VERSION 5.7 ;
BUSBITCHARS "[]" ;
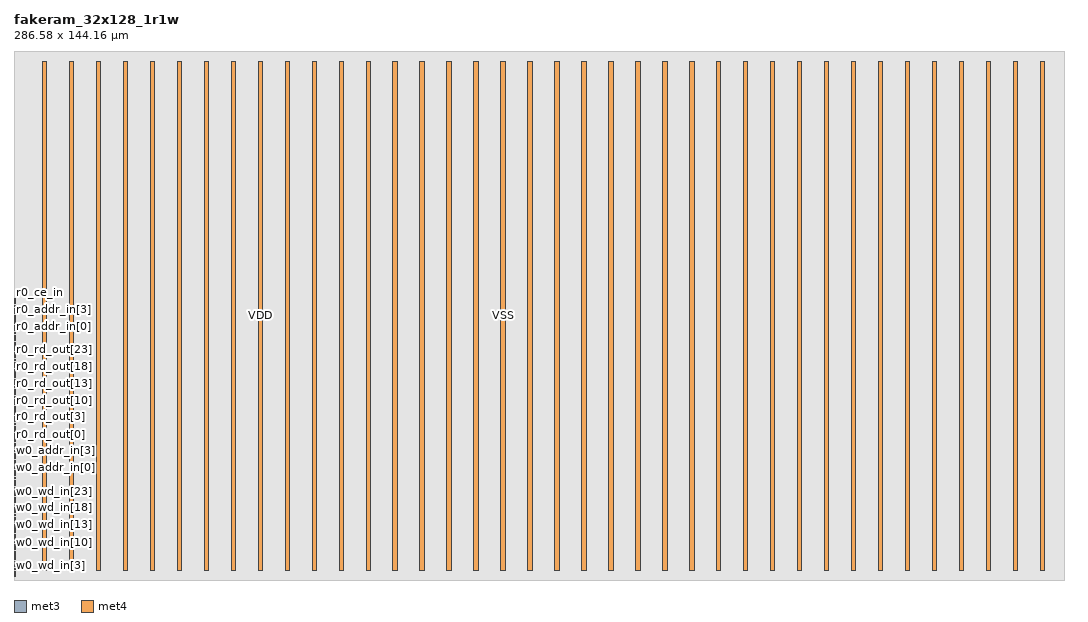
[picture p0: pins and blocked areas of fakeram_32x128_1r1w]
MACRO fakeram_32x128_1r1w
  FOREIGN fakeram_32x128_1r1w 0 0 ;
  SYMMETRY X Y R90 ;
  SIZE 286.580 BY 144.160 ;
  CLASS BLOCK ;
  PIN w0_wd_in[0]
    DIRECTION INPUT ;
    USE SIGNAL ;
    SHAPE ABUTMENT ;
    PORT
      LAYER met3 ;
      RECT 0.000 0.920 0.500 1.420 ;
    END
  END w0_wd_in[0]
  PIN w0_wd_in[1]
    DIRECTION INPUT ;
    USE SIGNAL ;
    SHAPE ABUTMENT ;
    PORT
      LAYER met3 ;
      RECT 0.000 1.840 0.500 2.340 ;
    END
  END w0_wd_in[1]
  PIN w0_wd_in[2]
    DIRECTION INPUT ;
    USE SIGNAL ;
    SHAPE ABUTMENT ;
    PORT
      LAYER met3 ;
      RECT 0.000 2.760 0.500 3.260 ;
    END
  END w0_wd_in[2]
  PIN w0_wd_in[3]
    DIRECTION INPUT ;
    USE SIGNAL ;
    SHAPE ABUTMENT ;
    PORT
      LAYER met3 ;
      RECT 0.000 3.680 0.500 4.180 ;
    END
  END w0_wd_in[3]
  PIN w0_wd_in[4]
    DIRECTION INPUT ;
    USE SIGNAL ;
    SHAPE ABUTMENT ;
    PORT
      LAYER met3 ;
      RECT 0.000 4.600 0.500 5.100 ;
    END
  END w0_wd_in[4]
  PIN w0_wd_in[5]
    DIRECTION INPUT ;
    USE SIGNAL ;
    SHAPE ABUTMENT ;
    PORT
      LAYER met3 ;
      RECT 0.000 5.520 0.500 6.020 ;
    END
  END w0_wd_in[5]
  PIN w0_wd_in[6]
    DIRECTION INPUT ;
    USE SIGNAL ;
    SHAPE ABUTMENT ;
    PORT
      LAYER met3 ;
      RECT 0.000 6.440 0.500 6.940 ;
    END
  END w0_wd_in[6]
  PIN w0_wd_in[7]
    DIRECTION INPUT ;
    USE SIGNAL ;
    SHAPE ABUTMENT ;
    PORT
      LAYER met3 ;
      RECT 0.000 7.360 0.500 7.860 ;
    END
  END w0_wd_in[7]
  PIN w0_wd_in[8]
    DIRECTION INPUT ;
    USE SIGNAL ;
    SHAPE ABUTMENT ;
    PORT
      LAYER met3 ;
      RECT 0.000 8.280 0.500 8.780 ;
    END
  END w0_wd_in[8]
  PIN w0_wd_in[9]
    DIRECTION INPUT ;
    USE SIGNAL ;
    SHAPE ABUTMENT ;
    PORT
      LAYER met3 ;
      RECT 0.000 9.200 0.500 9.700 ;
    END
  END w0_wd_in[9]
  PIN w0_wd_in[10]
    DIRECTION INPUT ;
    USE SIGNAL ;
    SHAPE ABUTMENT ;
    PORT
      LAYER met3 ;
      RECT 0.000 10.120 0.500 10.620 ;
    END
  END w0_wd_in[10]
  PIN w0_wd_in[11]
    DIRECTION INPUT ;
    USE SIGNAL ;
    SHAPE ABUTMENT ;
    PORT
      LAYER met3 ;
      RECT 0.000 11.040 0.500 11.540 ;
    END
  END w0_wd_in[11]
  PIN w0_wd_in[12]
    DIRECTION INPUT ;
    USE SIGNAL ;
    SHAPE ABUTMENT ;
    PORT
      LAYER met3 ;
      RECT 0.000 11.960 0.500 12.460 ;
    END
  END w0_wd_in[12]
  PIN w0_wd_in[13]
    DIRECTION INPUT ;
    USE SIGNAL ;
    SHAPE ABUTMENT ;
    PORT
      LAYER met3 ;
      RECT 0.000 12.880 0.500 13.380 ;
    END
  END w0_wd_in[13]
  PIN w0_wd_in[14]
    DIRECTION INPUT ;
    USE SIGNAL ;
    SHAPE ABUTMENT ;
    PORT
      LAYER met3 ;
      RECT 0.000 13.800 0.500 14.300 ;
    END
  END w0_wd_in[14]
  PIN w0_wd_in[15]
    DIRECTION INPUT ;
    USE SIGNAL ;
    SHAPE ABUTMENT ;
    PORT
      LAYER met3 ;
      RECT 0.000 14.720 0.500 15.220 ;
    END
  END w0_wd_in[15]
  PIN w0_wd_in[16]
    DIRECTION INPUT ;
    USE SIGNAL ;
    SHAPE ABUTMENT ;
    PORT
      LAYER met3 ;
      RECT 0.000 15.640 0.500 16.140 ;
    END
  END w0_wd_in[16]
  PIN w0_wd_in[17]
    DIRECTION INPUT ;
    USE SIGNAL ;
    SHAPE ABUTMENT ;
    PORT
      LAYER met3 ;
      RECT 0.000 16.560 0.500 17.060 ;
    END
  END w0_wd_in[17]
  PIN w0_wd_in[18]
    DIRECTION INPUT ;
    USE SIGNAL ;
    SHAPE ABUTMENT ;
    PORT
      LAYER met3 ;
      RECT 0.000 17.480 0.500 17.980 ;
    END
  END w0_wd_in[18]
  PIN w0_wd_in[19]
    DIRECTION INPUT ;
    USE SIGNAL ;
    SHAPE ABUTMENT ;
    PORT
      LAYER met3 ;
      RECT 0.000 18.400 0.500 18.900 ;
    END
  END w0_wd_in[19]
  PIN w0_wd_in[20]
    DIRECTION INPUT ;
    USE SIGNAL ;
    SHAPE ABUTMENT ;
    PORT
      LAYER met3 ;
      RECT 0.000 19.320 0.500 19.820 ;
    END
  END w0_wd_in[20]
  PIN w0_wd_in[21]
    DIRECTION INPUT ;
    USE SIGNAL ;
    SHAPE ABUTMENT ;
    PORT
      LAYER met3 ;
      RECT 0.000 20.240 0.500 20.740 ;
    END
  END w0_wd_in[21]
  PIN w0_wd_in[22]
    DIRECTION INPUT ;
    USE SIGNAL ;
    SHAPE ABUTMENT ;
    PORT
      LAYER met3 ;
      RECT 0.000 21.160 0.500 21.660 ;
    END
  END w0_wd_in[22]
  PIN w0_wd_in[23]
    DIRECTION INPUT ;
    USE SIGNAL ;
    SHAPE ABUTMENT ;
    PORT
      LAYER met3 ;
      RECT 0.000 22.080 0.500 22.580 ;
    END
  END w0_wd_in[23]
  PIN w0_wd_in[24]
    DIRECTION INPUT ;
    USE SIGNAL ;
    SHAPE ABUTMENT ;
    PORT
      LAYER met3 ;
      RECT 0.000 23.000 0.500 23.500 ;
    END
  END w0_wd_in[24]
  PIN w0_wd_in[25]
    DIRECTION INPUT ;
    USE SIGNAL ;
    SHAPE ABUTMENT ;
    PORT
      LAYER met3 ;
      RECT 0.000 23.920 0.500 24.420 ;
    END
  END w0_wd_in[25]
  PIN w0_wd_in[26]
    DIRECTION INPUT ;
    USE SIGNAL ;
    SHAPE ABUTMENT ;
    PORT
      LAYER met3 ;
      RECT 0.000 24.840 0.500 25.340 ;
    END
  END w0_wd_in[26]
  PIN w0_wd_in[27]
    DIRECTION INPUT ;
    USE SIGNAL ;
    SHAPE ABUTMENT ;
    PORT
      LAYER met3 ;
      RECT 0.000 25.760 0.500 26.260 ;
    END
  END w0_wd_in[27]
  PIN w0_wd_in[28]
    DIRECTION INPUT ;
    USE SIGNAL ;
    SHAPE ABUTMENT ;
    PORT
      LAYER met3 ;
      RECT 0.000 26.680 0.500 27.180 ;
    END
  END w0_wd_in[28]
  PIN w0_wd_in[29]
    DIRECTION INPUT ;
    USE SIGNAL ;
    SHAPE ABUTMENT ;
    PORT
      LAYER met3 ;
      RECT 0.000 27.600 0.500 28.100 ;
    END
  END w0_wd_in[29]
  PIN w0_wd_in[30]
    DIRECTION INPUT ;
    USE SIGNAL ;
    SHAPE ABUTMENT ;
    PORT
      LAYER met3 ;
      RECT 0.000 28.520 0.500 29.020 ;
    END
  END w0_wd_in[30]
  PIN w0_wd_in[31]
    DIRECTION INPUT ;
    USE SIGNAL ;
    SHAPE ABUTMENT ;
    PORT
      LAYER met3 ;
      RECT 0.000 29.440 0.500 29.940 ;
    END
  END w0_wd_in[31]
  PIN w0_addr_in[0]
    DIRECTION INPUT ;
    USE SIGNAL ;
    SHAPE ABUTMENT ;
    PORT
      LAYER met3 ;
      RECT 0.000 30.360 0.500 30.860 ;
    END
  END w0_addr_in[0]
  PIN w0_addr_in[1]
    DIRECTION INPUT ;
    USE SIGNAL ;
    SHAPE ABUTMENT ;
    PORT
      LAYER met3 ;
      RECT 0.000 31.280 0.500 31.780 ;
    END
  END w0_addr_in[1]
  PIN w0_addr_in[2]
    DIRECTION INPUT ;
    USE SIGNAL ;
    SHAPE ABUTMENT ;
    PORT
      LAYER met3 ;
      RECT 0.000 32.200 0.500 32.700 ;
    END
  END w0_addr_in[2]
  PIN w0_addr_in[3]
    DIRECTION INPUT ;
    USE SIGNAL ;
    SHAPE ABUTMENT ;
    PORT
      LAYER met3 ;
      RECT 0.000 33.120 0.500 33.620 ;
    END
  END w0_addr_in[3]
  PIN w0_addr_in[4]
    DIRECTION INPUT ;
    USE SIGNAL ;
    SHAPE ABUTMENT ;
    PORT
      LAYER met3 ;
      RECT 0.000 34.040 0.500 34.540 ;
    END
  END w0_addr_in[4]
  PIN w0_addr_in[5]
    DIRECTION INPUT ;
    USE SIGNAL ;
    SHAPE ABUTMENT ;
    PORT
      LAYER met3 ;
      RECT 0.000 34.960 0.500 35.460 ;
    END
  END w0_addr_in[5]
  PIN w0_addr_in[6]
    DIRECTION INPUT ;
    USE SIGNAL ;
    SHAPE ABUTMENT ;
    PORT
      LAYER met3 ;
      RECT 0.000 35.880 0.500 36.380 ;
    END
  END w0_addr_in[6]
  PIN w0_clk
    DIRECTION INPUT ;
    USE SIGNAL ;
    SHAPE ABUTMENT ;
    PORT
      LAYER met3 ;
      RECT 0.000 36.800 0.500 37.300 ;
    END
  END w0_clk
  PIN w0_ce_in
    DIRECTION INPUT ;
    USE SIGNAL ;
    SHAPE ABUTMENT ;
    PORT
      LAYER met3 ;
      RECT 0.000 37.720 0.500 38.220 ;
    END
  END w0_ce_in
  PIN w0_we_in
    DIRECTION INPUT ;
    USE SIGNAL ;
    SHAPE ABUTMENT ;
    PORT
      LAYER met3 ;
      RECT 0.000 38.640 0.500 39.140 ;
    END
  END w0_we_in
  PIN r0_rd_out[0]
    DIRECTION OUTPUT ;
    USE SIGNAL ;
    SHAPE ABUTMENT ;
    PORT
      LAYER met3 ;
      RECT 0.000 39.560 0.500 40.060 ;
    END
  END r0_rd_out[0]
  PIN r0_rd_out[1]
    DIRECTION OUTPUT ;
    USE SIGNAL ;
    SHAPE ABUTMENT ;
    PORT
      LAYER met3 ;
      RECT 0.000 40.480 0.500 40.980 ;
    END
  END r0_rd_out[1]
  PIN r0_rd_out[2]
    DIRECTION OUTPUT ;
    USE SIGNAL ;
    SHAPE ABUTMENT ;
    PORT
      LAYER met3 ;
      RECT 0.000 41.400 0.500 41.900 ;
    END
  END r0_rd_out[2]
  PIN r0_rd_out[3]
    DIRECTION OUTPUT ;
    USE SIGNAL ;
    SHAPE ABUTMENT ;
    PORT
      LAYER met3 ;
      RECT 0.000 42.320 0.500 42.820 ;
    END
  END r0_rd_out[3]
  PIN r0_rd_out[4]
    DIRECTION OUTPUT ;
    USE SIGNAL ;
    SHAPE ABUTMENT ;
    PORT
      LAYER met3 ;
      RECT 0.000 43.240 0.500 43.740 ;
    END
  END r0_rd_out[4]
  PIN r0_rd_out[5]
    DIRECTION OUTPUT ;
    USE SIGNAL ;
    SHAPE ABUTMENT ;
    PORT
      LAYER met3 ;
      RECT 0.000 44.160 0.500 44.660 ;
    END
  END r0_rd_out[5]
  PIN r0_rd_out[6]
    DIRECTION OUTPUT ;
    USE SIGNAL ;
    SHAPE ABUTMENT ;
    PORT
      LAYER met3 ;
      RECT 0.000 45.080 0.500 45.580 ;
    END
  END r0_rd_out[6]
  PIN r0_rd_out[7]
    DIRECTION OUTPUT ;
    USE SIGNAL ;
    SHAPE ABUTMENT ;
    PORT
      LAYER met3 ;
      RECT 0.000 46.000 0.500 46.500 ;
    END
  END r0_rd_out[7]
  PIN r0_rd_out[8]
    DIRECTION OUTPUT ;
    USE SIGNAL ;
    SHAPE ABUTMENT ;
    PORT
      LAYER met3 ;
      RECT 0.000 46.920 0.500 47.420 ;
    END
  END r0_rd_out[8]
  PIN r0_rd_out[9]
    DIRECTION OUTPUT ;
    USE SIGNAL ;
    SHAPE ABUTMENT ;
    PORT
      LAYER met3 ;
      RECT 0.000 47.840 0.500 48.340 ;
    END
  END r0_rd_out[9]
  PIN r0_rd_out[10]
    DIRECTION OUTPUT ;
    USE SIGNAL ;
    SHAPE ABUTMENT ;
    PORT
      LAYER met3 ;
      RECT 0.000 48.760 0.500 49.260 ;
    END
  END r0_rd_out[10]
  PIN r0_rd_out[11]
    DIRECTION OUTPUT ;
    USE SIGNAL ;
    SHAPE ABUTMENT ;
    PORT
      LAYER met3 ;
      RECT 0.000 49.680 0.500 50.180 ;
    END
  END r0_rd_out[11]
  PIN r0_rd_out[12]
    DIRECTION OUTPUT ;
    USE SIGNAL ;
    SHAPE ABUTMENT ;
    PORT
      LAYER met3 ;
      RECT 0.000 50.600 0.500 51.100 ;
    END
  END r0_rd_out[12]
  PIN r0_rd_out[13]
    DIRECTION OUTPUT ;
    USE SIGNAL ;
    SHAPE ABUTMENT ;
    PORT
      LAYER met3 ;
      RECT 0.000 51.520 0.500 52.020 ;
    END
  END r0_rd_out[13]
  PIN r0_rd_out[14]
    DIRECTION OUTPUT ;
    USE SIGNAL ;
    SHAPE ABUTMENT ;
    PORT
      LAYER met3 ;
      RECT 0.000 52.440 0.500 52.940 ;
    END
  END r0_rd_out[14]
  PIN r0_rd_out[15]
    DIRECTION OUTPUT ;
    USE SIGNAL ;
    SHAPE ABUTMENT ;
    PORT
      LAYER met3 ;
      RECT 0.000 53.360 0.500 53.860 ;
    END
  END r0_rd_out[15]
  PIN r0_rd_out[16]
    DIRECTION OUTPUT ;
    USE SIGNAL ;
    SHAPE ABUTMENT ;
    PORT
      LAYER met3 ;
      RECT 0.000 54.280 0.500 54.780 ;
    END
  END r0_rd_out[16]
  PIN r0_rd_out[17]
    DIRECTION OUTPUT ;
    USE SIGNAL ;
    SHAPE ABUTMENT ;
    PORT
      LAYER met3 ;
      RECT 0.000 55.200 0.500 55.700 ;
    END
  END r0_rd_out[17]
  PIN r0_rd_out[18]
    DIRECTION OUTPUT ;
    USE SIGNAL ;
    SHAPE ABUTMENT ;
    PORT
      LAYER met3 ;
      RECT 0.000 56.120 0.500 56.620 ;
    END
  END r0_rd_out[18]
  PIN r0_rd_out[19]
    DIRECTION OUTPUT ;
    USE SIGNAL ;
    SHAPE ABUTMENT ;
    PORT
      LAYER met3 ;
      RECT 0.000 57.040 0.500 57.540 ;
    END
  END r0_rd_out[19]
  PIN r0_rd_out[20]
    DIRECTION OUTPUT ;
    USE SIGNAL ;
    SHAPE ABUTMENT ;
    PORT
      LAYER met3 ;
      RECT 0.000 57.960 0.500 58.460 ;
    END
  END r0_rd_out[20]
  PIN r0_rd_out[21]
    DIRECTION OUTPUT ;
    USE SIGNAL ;
    SHAPE ABUTMENT ;
    PORT
      LAYER met3 ;
      RECT 0.000 58.880 0.500 59.380 ;
    END
  END r0_rd_out[21]
  PIN r0_rd_out[22]
    DIRECTION OUTPUT ;
    USE SIGNAL ;
    SHAPE ABUTMENT ;
    PORT
      LAYER met3 ;
      RECT 0.000 59.800 0.500 60.300 ;
    END
  END r0_rd_out[22]
  PIN r0_rd_out[23]
    DIRECTION OUTPUT ;
    USE SIGNAL ;
    SHAPE ABUTMENT ;
    PORT
      LAYER met3 ;
      RECT 0.000 60.720 0.500 61.220 ;
    END
  END r0_rd_out[23]
  PIN r0_rd_out[24]
    DIRECTION OUTPUT ;
    USE SIGNAL ;
    SHAPE ABUTMENT ;
    PORT
      LAYER met3 ;
      RECT 0.000 61.640 0.500 62.140 ;
    END
  END r0_rd_out[24]
  PIN r0_rd_out[25]
    DIRECTION OUTPUT ;
    USE SIGNAL ;
    SHAPE ABUTMENT ;
    PORT
      LAYER met3 ;
      RECT 0.000 62.560 0.500 63.060 ;
    END
  END r0_rd_out[25]
  PIN r0_rd_out[26]
    DIRECTION OUTPUT ;
    USE SIGNAL ;
    SHAPE ABUTMENT ;
    PORT
      LAYER met3 ;
      RECT 0.000 63.480 0.500 63.980 ;
    END
  END r0_rd_out[26]
  PIN r0_rd_out[27]
    DIRECTION OUTPUT ;
    USE SIGNAL ;
    SHAPE ABUTMENT ;
    PORT
      LAYER met3 ;
      RECT 0.000 64.400 0.500 64.900 ;
    END
  END r0_rd_out[27]
  PIN r0_rd_out[28]
    DIRECTION OUTPUT ;
    USE SIGNAL ;
    SHAPE ABUTMENT ;
    PORT
      LAYER met3 ;
      RECT 0.000 65.320 0.500 65.820 ;
    END
  END r0_rd_out[28]
  PIN r0_rd_out[29]
    DIRECTION OUTPUT ;
    USE SIGNAL ;
    SHAPE ABUTMENT ;
    PORT
      LAYER met3 ;
      RECT 0.000 66.240 0.500 66.740 ;
    END
  END r0_rd_out[29]
  PIN r0_rd_out[30]
    DIRECTION OUTPUT ;
    USE SIGNAL ;
    SHAPE ABUTMENT ;
    PORT
      LAYER met3 ;
      RECT 0.000 67.160 0.500 67.660 ;
    END
  END r0_rd_out[30]
  PIN r0_rd_out[31]
    DIRECTION OUTPUT ;
    USE SIGNAL ;
    SHAPE ABUTMENT ;
    PORT
      LAYER met3 ;
      RECT 0.000 68.080 0.500 68.580 ;
    END
  END r0_rd_out[31]
  PIN r0_addr_in[0]
    DIRECTION INPUT ;
    USE SIGNAL ;
    SHAPE ABUTMENT ;
    PORT
      LAYER met3 ;
      RECT 0.000 69.000 0.500 69.500 ;
    END
  END r0_addr_in[0]
  PIN r0_addr_in[1]
    DIRECTION INPUT ;
    USE SIGNAL ;
    SHAPE ABUTMENT ;
    PORT
      LAYER met3 ;
      RECT 0.000 69.920 0.500 70.420 ;
    END
  END r0_addr_in[1]
  PIN r0_addr_in[2]
    DIRECTION INPUT ;
    USE SIGNAL ;
    SHAPE ABUTMENT ;
    PORT
      LAYER met3 ;
      RECT 0.000 70.840 0.500 71.340 ;
    END
  END r0_addr_in[2]
  PIN r0_addr_in[3]
    DIRECTION INPUT ;
    USE SIGNAL ;
    SHAPE ABUTMENT ;
    PORT
      LAYER met3 ;
      RECT 0.000 71.760 0.500 72.260 ;
    END
  END r0_addr_in[3]
  PIN r0_addr_in[4]
    DIRECTION INPUT ;
    USE SIGNAL ;
    SHAPE ABUTMENT ;
    PORT
      LAYER met3 ;
      RECT 0.000 72.680 0.500 73.180 ;
    END
  END r0_addr_in[4]
  PIN r0_addr_in[5]
    DIRECTION INPUT ;
    USE SIGNAL ;
    SHAPE ABUTMENT ;
    PORT
      LAYER met3 ;
      RECT 0.000 73.600 0.500 74.100 ;
    END
  END r0_addr_in[5]
  PIN r0_addr_in[6]
    DIRECTION INPUT ;
    USE SIGNAL ;
    SHAPE ABUTMENT ;
    PORT
      LAYER met3 ;
      RECT 0.000 74.520 0.500 75.020 ;
    END
  END r0_addr_in[6]
  PIN r0_clk
    DIRECTION INPUT ;
    USE SIGNAL ;
    SHAPE ABUTMENT ;
    PORT
      LAYER met3 ;
      RECT 0.000 75.440 0.500 75.940 ;
    END
  END r0_clk
  PIN r0_ce_in
    DIRECTION INPUT ;
    USE SIGNAL ;
    SHAPE ABUTMENT ;
    PORT
      LAYER met3 ;
      RECT 0.000 76.360 0.500 76.860 ;
    END
  END r0_ce_in
  PIN VDD
    DIRECTION INOUT ;
    USE POWER ;
    PORT
      LAYER met4 ;
      RECT 7.760 2.720 8.960 141.440 ;
      RECT 22.480 2.720 23.680 141.440 ;
      RECT 37.200 2.720 38.400 141.440 ;
      RECT 51.920 2.720 53.120 141.440 ;
      RECT 66.640 2.720 67.840 141.440 ;
      RECT 81.360 2.720 82.560 141.440 ;
      RECT 96.080 2.720 97.280 141.440 ;
      RECT 110.800 2.720 112.000 141.440 ;
      RECT 125.520 2.720 126.720 141.440 ;
      RECT 140.240 2.720 141.440 141.440 ;
      RECT 154.960 2.720 156.160 141.440 ;
      RECT 169.680 2.720 170.880 141.440 ;
      RECT 184.400 2.720 185.600 141.440 ;
      RECT 199.120 2.720 200.320 141.440 ;
      RECT 213.840 2.720 215.040 141.440 ;
      RECT 228.560 2.720 229.760 141.440 ;
      RECT 243.280 2.720 244.480 141.440 ;
      RECT 258.000 2.720 259.200 141.440 ;
      RECT 272.720 2.720 273.920 141.440 ;
    END
  END VDD
  PIN VSS
    DIRECTION INOUT ;
    USE GROUND ;
    PORT
      LAYER met4 ;
      RECT 15.120 2.720 16.320 141.440 ;
      RECT 29.840 2.720 31.040 141.440 ;
      RECT 44.560 2.720 45.760 141.440 ;
      RECT 59.280 2.720 60.480 141.440 ;
      RECT 74.000 2.720 75.200 141.440 ;
      RECT 88.720 2.720 89.920 141.440 ;
      RECT 103.440 2.720 104.640 141.440 ;
      RECT 118.160 2.720 119.360 141.440 ;
      RECT 132.880 2.720 134.080 141.440 ;
      RECT 147.600 2.720 148.800 141.440 ;
      RECT 162.320 2.720 163.520 141.440 ;
      RECT 177.040 2.720 178.240 141.440 ;
      RECT 191.760 2.720 192.960 141.440 ;
      RECT 206.480 2.720 207.680 141.440 ;
      RECT 221.200 2.720 222.400 141.440 ;
      RECT 235.920 2.720 237.120 141.440 ;
      RECT 250.640 2.720 251.840 141.440 ;
      RECT 265.360 2.720 266.560 141.440 ;
      RECT 280.080 2.720 281.280 141.440 ;
    END
  END VSS
  OBS
    LAYER met1 ;
      RECT 0.000 0.000 286.580 144.160 ;
    LAYER met2 ;
      RECT 0.000 0.000 286.580 144.160 ;
    LAYER met3 ;
      RECT 0.000 0.000 286.580 144.160 ;
  END
END fakeram_32x128_1r1w
END LIBRARY
